VERSION 5.7 ;
  NOWIREEXTENSIONATPIN ON ;
  DIVIDERCHAR "/" ;
  BUSBITCHARS "[]" ;
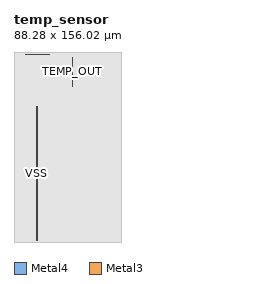
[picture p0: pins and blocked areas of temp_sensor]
MACRO temp_sensor
  CLASS BLOCK ;
  FOREIGN temp_sensor ;
  ORIGIN 44.160 3.940 ;
  SIZE 88.280 BY 156.020 ;
  PIN TEMP_OUT
    ANTENNAGATEAREA 2.400000 ;
    ANTENNADIFFAREA 5.400000 ;
    PORT
      LAYER Metal4 ;
        RECT 3.920 123.680 4.200 147.880 ;
    END
  END TEMP_OUT
  PIN VSS
    USE GROUND ;
    PORT
      LAYER Metal4 ;
        RECT -25.800 -2.800 -25.240 107.080 ;
    END
  END VSS
  PIN VDD
    USE POWER ;
    PORT
      LAYER Metal3 ;
        RECT -34.980 149.780 -15.040 150.340 ;
    END
  END VDD
  OBS
      LAYER Nwell ;
        RECT -40.940 107.620 40.940 147.890 ;
      LAYER Metal1 ;
        RECT -40.710 0.270 40.710 147.680 ;
      LAYER Metal2 ;
        RECT -40.710 1.910 40.710 147.680 ;
      LAYER Metal3 ;
        RECT -44.160 150.640 44.120 151.360 ;
        RECT -44.160 149.480 -35.280 150.640 ;
        RECT -14.740 149.480 44.120 150.640 ;
        RECT -44.160 -3.220 44.120 149.480 ;
      LAYER Metal4 ;
        RECT -44.130 148.180 44.090 151.330 ;
        RECT -44.130 123.380 3.620 148.180 ;
        RECT 4.500 123.380 44.090 148.180 ;
        RECT -44.130 107.380 44.090 123.380 ;
        RECT -44.130 -3.100 -26.100 107.380 ;
        RECT -24.940 -3.100 44.090 107.380 ;
        RECT -44.130 -3.220 44.090 -3.100 ;
      LAYER Metal5 ;
        RECT -44.130 -3.940 44.090 152.080 ;
  END
END temp_sensor
END LIBRARY

